# Small hand-written library for the LEF/DEF reader tests.
VERSION 5.8 ;
BUSBITCHARS "[]" ;
DIVIDERCHAR "/" ;

UNITS
  DATABASE MICRONS 1000 ;
END UNITS

MANUFACTURINGGRID 0.005 ;

SITE core
  CLASS CORE ;
  SYMMETRY Y ;
  SIZE 0.2 BY 2.0 ;
END core

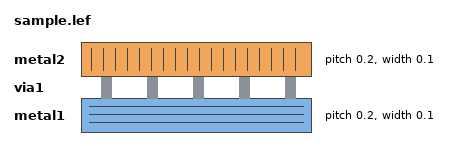
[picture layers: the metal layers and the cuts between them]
LAYER metal1
  TYPE ROUTING ;
  DIRECTION HORIZONTAL ;
  PITCH 0.2 ;
  WIDTH 0.1 ;
  PROPERTY LEF58_TYPE "TYPE MIMCAP ; END" ;
END metal1

LAYER via1
  TYPE CUT ;
END via1

LAYER metal2
  TYPE ROUTING ;
  DIRECTION VERTICAL ;
  PITCH 0.2 ;
  WIDTH 0.1 ;
END metal2

VIA via12 DEFAULT
  LAYER metal1 ;
    RECT -0.05 -0.05 0.05 0.05 ;
  LAYER via1 ;
    RECT -0.05 -0.05 0.05 0.05 ;
  LAYER metal2 ;
    RECT -0.05 -0.05 0.05 0.05 ;
END via12

SPACING
  SAMENET metal1 metal1 0.1 ;
END SPACING

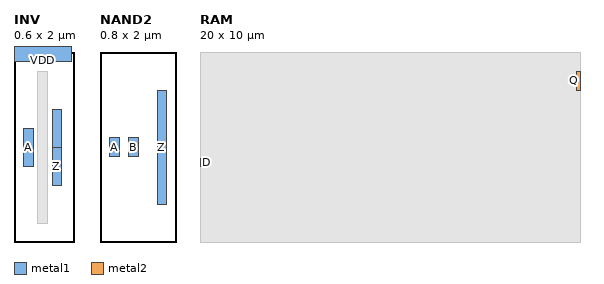
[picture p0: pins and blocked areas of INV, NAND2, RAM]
MACRO INV
  CLASS CORE ;
  FOREIGN INV 0 0 ;
  ORIGIN 0 0 ;
  SIZE 0.6 BY 2.0 ;
  SYMMETRY X Y ;
  SITE core ;
  PIN A
    DIRECTION INPUT ;
    USE SIGNAL ;
    PORT
      LAYER metal1 ;
        RECT 0.1 0.8 0.2 1.2 ;
    END
  END A
  PIN Z
    DIRECTION OUTPUT ;
    USE SIGNAL ;
    PORT
      LAYER metal1 ;
        RECT 0.4 0.6 0.5 1.0 ;
        RECT 0.4 1.0 0.5 1.4 ;
    END
  END Z
  PIN VDD
    DIRECTION INOUT ;
    USE POWER ;
    SHAPE ABUTMENT ;
    PORT
      LAYER metal1 ;
        RECT 0 1.9 0.6 2.1 ;
    END
  END VDD
  OBS
    LAYER metal1 ;
      RECT 0.25 0.2 0.35 1.8 ;
  END
END INV

MACRO NAND2
  CLASS CORE ;
  SIZE 0.8 BY 2.0 ;
  SITE core ;
  PIN A DIRECTION INPUT ; PORT LAYER metal1 ; RECT 0.1 0.9 0.2 1.1 ; END END A
  PIN B DIRECTION INPUT ; PORT LAYER metal1 ; RECT 0.3 0.9 0.4 1.1 ; END END B
  PIN Z
    DIRECTION OUTPUT TRISTATE ;
    PORT
      LAYER metal1 ;
        POLYGON 0.6 0.4 0.7 0.4 0.7 1.6 0.6 1.6 ;
    END
  END Z
END NAND2

# A block with a non-zero ORIGIN: shapes are shifted by (+1, +2) microns.
MACRO RAM
  CLASS BLOCK ;
  ORIGIN 1 2 ;
  SIZE 20 BY 10 ;
  PIN D
    DIRECTION INPUT ;
    PORT
      LAYER metal2 ;
        RECT MASK 1 -1 2 -0.8 2.4 ;
    END
  END D
  PIN Q
    DIRECTION OUTPUT ;
    PORT
      LAYER metal2 ;
        RECT 18.8 6 19 7 ;
    END
  END Q
  OBS
    LAYER metal1 ;
      RECT -1 -2 19 8 ;
  END
END RAM

END LIBRARY
